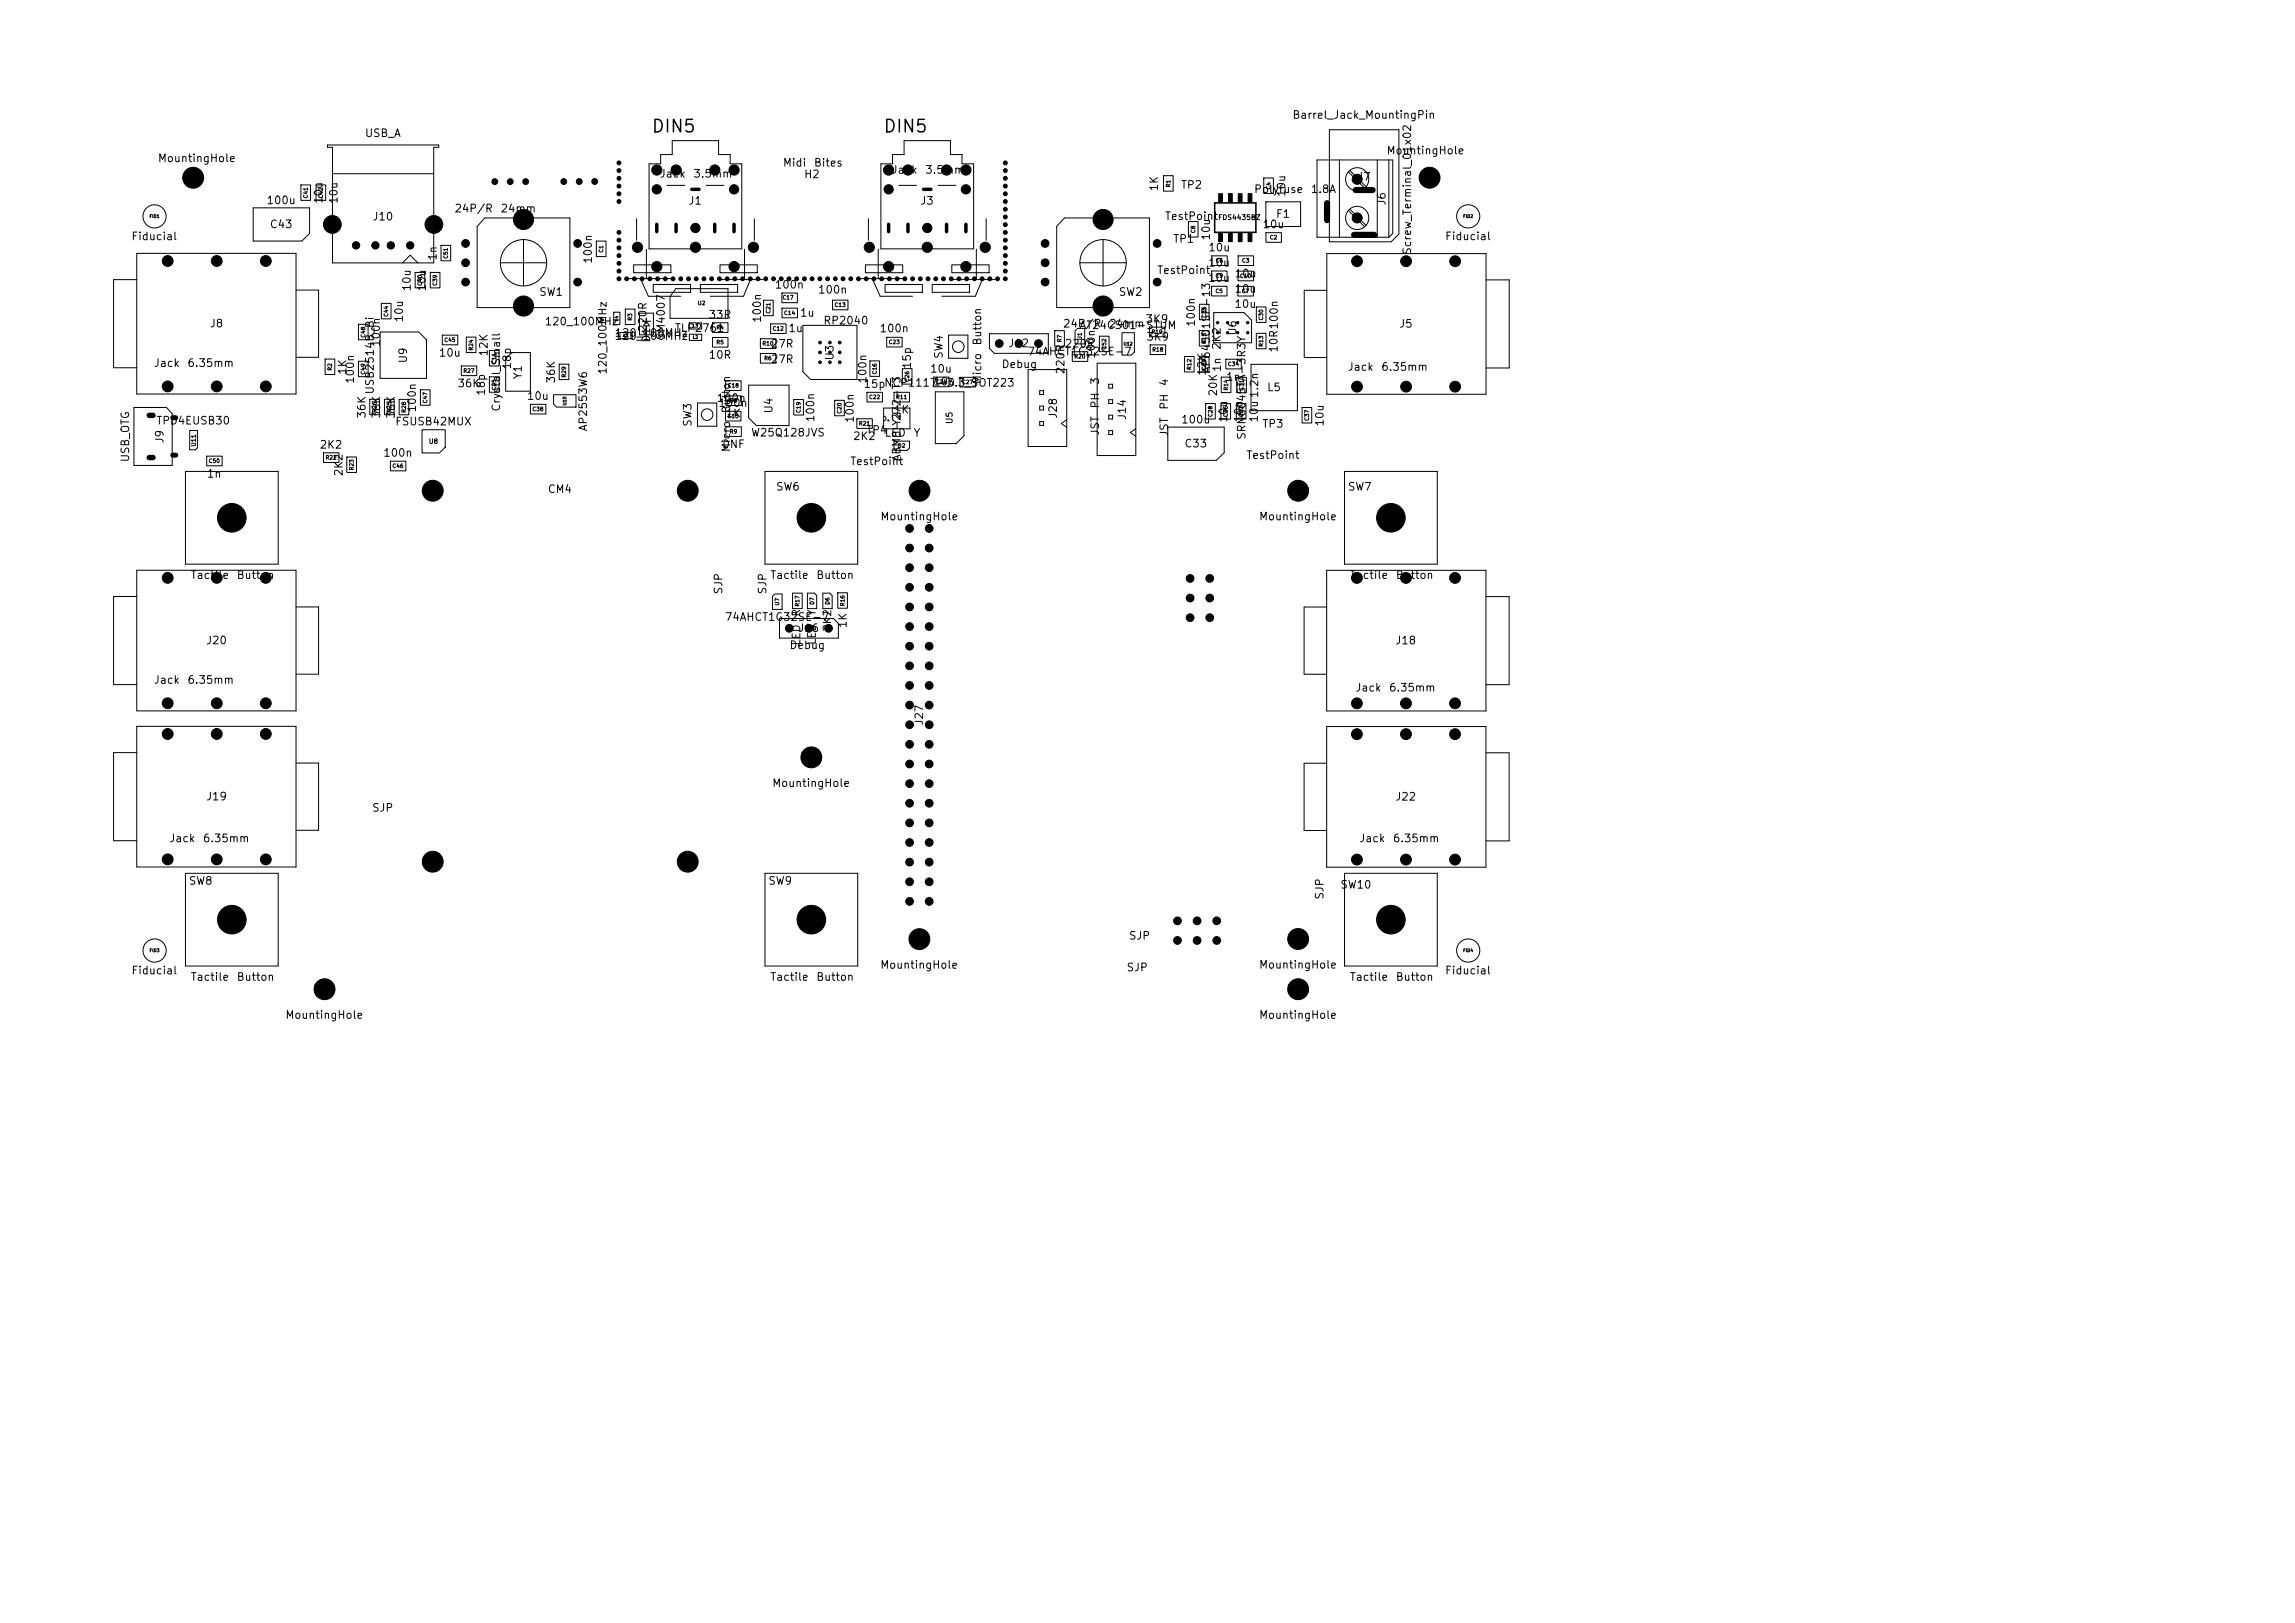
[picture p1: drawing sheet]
<svg xmlns="http://www.w3.org/2000/svg" width="297mm" height="210mm" viewBox="0 0 297 210" stroke-linecap="round" stroke-linejoin="round" font-family="sans-serif">
<defs><g id="words">
<g font-size="1.6">
<text x="84.2" y="17.5">DIN5</text>
<text x="114.2" y="17.5">DIN5</text>
</g>
<g font-size="1">
<text x="47.1" y="18">USB_A</text>
<text x="167.2" y="15.6">Barrel_Jack_MountingPin</text>
<text x="20.4" y="21.2">MountingHole</text>
<text x="23.9" y="23.7">H1</text>
<text x="85.3" y="23.2">Jack</text>
<text x="89.6" y="23.2">3.5mm</text>
<text x="101.2" y="21.8">Midi</text>
<text x="104" y="23.3">H2</text>
<text x="105.2" y="21.8">Bites</text>
<text x="115.3" y="22.7">Jack</text>
<text x="119.6" y="22.7">3.5mm</text>
<text x="175.6" y="23.6">J7</text>
<text x="179.4" y="20.2">MountingHole</text>
<text x="183.9" y="23.7">H3</text>
<text x="34.4" y="26.7">100u</text>
<text x="34.8" y="29.8">C43</text>
<text x="42" y="26.5" transform="rotate(-90 42 26.5)">10u</text>
<text x="43.9" y="26.5" transform="rotate(-90 43.9 26.5)">10u</text>
<text x="48.1" y="28.8">J10</text>
<text x="58.7" y="27.7">24P/R</text>
<text x="64.7" y="27.7">24mm</text>
<text x="89" y="26.7">J1</text>
<text x="119" y="26.7">J3</text>
<text x="150.1" y="24.8" transform="rotate(-90 150.1 24.8)">1K</text>
<text x="150.7" y="28.7">TestPoint</text>
<text x="152.7" y="24.7">TP2</text>
<text x="162.2" y="25.2">Polyfuse</text>
<text x="163.3" y="29.8">10u</text>
<text x="165" y="28.4">F1</text>
<text x="166.6" y="25.6" transform="rotate(-90 166.6 25.6)">10u</text>
<text x="169.6" y="25.2">1.8A</text>
<text x="179.6" y="26.7" transform="rotate(-90 179.6 26.7)">J6</text>
<text x="16.9" y="31.3">Fiducial</text>
<text x="56.7" y="33.8" transform="rotate(-90 56.7 33.8)">1n</text>
<text x="76.8" y="34.2" transform="rotate(-90 76.8 34.2)">100n</text>
<text x="149.7" y="35.7">TestPoint</text>
<text x="151.7" y="31.7">TP1</text>
<text x="156.3" y="34.7">10u</text>
<text x="156.3" y="32.8">10u</text>
<text x="156.8" y="31.2" transform="rotate(-90 156.8 31.2)">10u</text>
<text x="182.9" y="33" transform="rotate(-90 182.9 33)">Screw_Terminal_01x02</text>
<text x="186.9" y="31.3">Fiducial</text>
<text x="52.4" y="41.8" transform="rotate(-90 52.4 41.8)">10u</text>
<text x="53.4" y="37.8" transform="rotate(-90 53.4 37.8)">10u</text>
<text x="55.4" y="37.8" transform="rotate(-90 55.4 37.8)">10u</text>
<text x="69.7" y="38.5">SW1</text>
<text x="91.6" y="41.5">33R</text>
<text x="98.7" y="41.9" transform="rotate(-90 98.7 41.9)">100n</text>
<text x="100.2" y="37.6">100n</text>
<text x="103.4" y="41.2">1u</text>
<text x="105.8" y="38.2">100n</text>
<text x="144.7" y="38.5">SW2</text>
<text x="156.3" y="36.7">10u</text>
<text x="159.7" y="40.1">10u</text>
<text x="159.7" y="38.1">10u</text>
<text x="159.7" y="36.1">10u</text>
<text x="19.8" y="47.7">Jack</text>
<text x="24.2" y="47.7">6.35mm</text>
<text x="27.1" y="42.6">J8</text>
<text x="49.4" y="45" transform="rotate(-90 49.4 45)">100n</text>
<text x="52.9" y="47.1" transform="rotate(-90 52.9 47.1)">U9</text>
<text x="56.7" y="46.4">10u</text>
<text x="63.3" y="46.2" transform="rotate(-90 63.3 46.2)">12K</text>
<text x="66.4" y="47.9" transform="rotate(-90 66.4 47.9)">18p</text>
<text x="70.4" y="42.3">120_100MHz</text>
<text x="79.4" y="43.8">120_100MHz</text>
<text x="79.4" y="44.2">120_100MHz</text>
<text x="83.9" y="43" transform="rotate(-90 83.9 43)">220R</text>
<text x="84.4" y="44.4" transform="rotate(-90 84.4 44.4)">D1</text>
<text x="86.3" y="44.1" transform="rotate(-90 86.3 44.1)">SM4007</text>
<text x="87.2" y="43.2">TLP2761</text>
<text x="91.6" y="46.7">10R</text>
<text x="99.7" y="45.2">27R</text>
<text x="99.7" y="47.2">27R</text>
<text x="101.9" y="43.2">1u</text>
<text x="106.5" y="42.2">RP2040</text>
<text x="108.1" y="46.7" transform="rotate(-90 108.1 46.7)">U3</text>
<text x="113.7" y="43.2">100n</text>
<text x="118.1" y="47.8" transform="rotate(-90 118.1 47.8)">15p</text>
<text x="122.2" y="46.5" transform="rotate(-90 122.2 46.5)">SW4</text>
<text x="127.2" y="44.8" transform="rotate(-90 127.2 44.8)">Button</text>
<text x="129.5" y="47.9">Debug</text>
<text x="130.4" y="45.2">J12</text>
<text x="132.9" y="46.2">74AHCT1G32SE-7</text>
<text x="137.5" y="42.6">24P/R</text>
<text x="137.7" y="45.2">220R</text>
<text x="139.6" y="42.8">AT24CS01-STUM</text>
<text x="141.9" y="46.5" transform="rotate(-90 141.9 46.5)">100n</text>
<text x="143.4" y="42.6">24mm</text>
<text x="148.2" y="42">3K9</text>
<text x="148.3" y="44.3">3K9</text>
<text x="154.9" y="42.4" transform="rotate(-90 154.9 42.4)">100n</text>
<text x="158.2" y="45.3" transform="rotate(-90 158.2 45.3)">2K2</text>
<text x="160.2" y="43.5" transform="rotate(-90 160.2 43.5)">U6</text>
<text x="165.6" y="45.7" transform="rotate(-90 165.6 45.7)">10R100n</text>
<text x="181" y="42.6">J5</text>
<text x="45.1" y="48.6" transform="rotate(-90 45.1 48.6)">1K</text>
<text x="46.1" y="49.7" transform="rotate(-90 46.1 49.7)">100n</text>
<text x="48.6" y="51.1" transform="rotate(-90 48.6 51.1)">USB2514B_Bi</text>
<text x="54.1" y="53.4" transform="rotate(-90 54.1 53.4)">100n</text>
<text x="59.1" y="50.4">36K</text>
<text x="63" y="51.3" transform="rotate(-90 63 51.3)">18p</text>
<text x="65" y="53.3" transform="rotate(-90 65 53.3)">Crystal_Small</text>
<text x="67.8" y="49.1" transform="rotate(-90 67.8 49.1)">Y1</text>
<text x="68.1" y="52">10u</text>
<text x="72.1" y="49.7" transform="rotate(-90 72.1 49.7)">36K</text>
<text x="78.7" y="48.6" transform="rotate(-90 78.7 48.6)">120_100MHz</text>
<text x="92.7" y="52.3">100n</text>
<text x="92.9" y="52.9">100n</text>
<text x="94.7" y="53.6" transform="rotate(-90 94.7 53.6)">Button</text>
<text x="100.2" y="53.6" transform="rotate(-90 100.2 53.6)">U4</text>
<text x="111.7" y="50.4">15pNCP1117-3.3_SOT223</text>
<text x="112.4" y="49.7" transform="rotate(-90 112.4 49.7)">100n</text>
<text x="115.6" y="53.8">1K</text>
<text x="120.3" y="48.5">10u</text>
<text x="120.7" y="50.1">10u</text>
<text x="127.2" y="49.8" transform="rotate(-90 127.2 49.8)">Micro</text>
<text x="138" y="48.5" transform="rotate(-90 138 48.5)">220R</text>
<text x="142.5" y="52.9" transform="rotate(-90 142.5 52.9)">PH</text>
<text x="142.5" y="49.9" transform="rotate(-90 142.5 49.9)">3</text>
<text x="151.4" y="53.1" transform="rotate(-90 151.4 53.1)">PH</text>
<text x="151.4" y="50" transform="rotate(-90 151.4 50)">4</text>
<text x="156.3" y="48.7" transform="rotate(-90 156.3 48.7)">12K</text>
<text x="156.8" y="48.4" transform="rotate(-90 156.8 48.4)">AP64501SP-13</text>
<text x="157.7" y="51.4" transform="rotate(-90 157.7 51.4)">20K</text>
<text x="158.2" y="48.2" transform="rotate(-90 158.2 48.2)">1n</text>
<text x="158.6" y="49.5">1n</text>
<text x="163.9" y="50.9">L5</text>
<text x="174.3" y="48.2">Jack</text>
<text x="178.7" y="48.2">6.35mm</text>
<text x="17" y="59.9" transform="rotate(-90 17 59.9)">USB_OTG</text>
<text x="20.1" y="55.2">TPD4EUSB30</text>
<text x="21.4" y="57.5" transform="rotate(-90 21.4 57.5)">J9</text>
<text x="41.3" y="58.3">2K2</text>
<text x="47.6" y="54.2" transform="rotate(-90 47.6 54.2)">36K</text>
<text x="49.5" y="54.2" transform="rotate(-90 49.5 54.2)">36K</text>
<text x="49.5" y="59.3">100n</text>
<text x="51.1" y="55.3">FSUSB42MUX</text>
<text x="51.4" y="54.3" transform="rotate(-90 51.4 54.3)">36K</text>
<text x="76.2" y="55.9" transform="rotate(-90 76.2 55.9)">AP2553W6</text>
<text x="89.7" y="55.3" transform="rotate(-90 89.7 55.3)">SW3</text>
<text x="93.4" y="58.2">DNF</text>
<text x="93.8" y="54.2">1K</text>
<text x="94.7" y="58.6" transform="rotate(-90 94.7 58.6)">Micro</text>
<text x="97.1" y="56.7">W25Q128JVS</text>
<text x="105.6" y="54.7" transform="rotate(-90 105.6 54.7)">100n</text>
<text x="110.3" y="57.2">2K2</text>
<text x="110.7" y="54.8" transform="rotate(-90 110.7 54.8)">100n</text>
<text x="112" y="56.4">TP4</text>
<text x="114.4" y="56.8">LED</text>
<text x="116.8" y="59.8" transform="rotate(-90 116.8 59.8)">ABM8-272-T3</text>
<text x="116.8" y="55.2" transform="rotate(-90 116.8 55.2)">Y2</text>
<text x="118.1" y="56.8">Y</text>
<text x="137" y="54.3" transform="rotate(-90 137 54.3)">J28</text>
<text x="142.5" y="56.4" transform="rotate(-90 142.5 56.4)">JST</text>
<text x="146" y="54.4" transform="rotate(-90 146 54.4)">J14</text>
<text x="151.4" y="56.6" transform="rotate(-90 151.4 56.6)">JST</text>
<text x="152.8" y="55">100u</text>
<text x="153.2" y="58.1">C33</text>
<text x="159.1" y="54.7" transform="rotate(-90 159.1 54.7)">10u</text>
<text x="161" y="54.8" transform="rotate(-90 161 54.8)">10u</text>
<text x="161.2" y="59.6">TestPoint</text>
<text x="161.4" y="57" transform="rotate(-90 161.4 57)">SRN6045TA-3R3Y</text>
<text x="163" y="54.7" transform="rotate(-90 163 54.7)">10u 1.2n</text>
<text x="163.3" y="55.6">TP3</text>
<text x="171.5" y="55.3" transform="rotate(-90 171.5 55.3)">10u</text>
<text x="26.7" y="62.1">1n</text>
<text x="44.6" y="61.7" transform="rotate(-90 44.6 61.7)">2K2</text>
<text x="70.8" y="64">CM4</text>
<text x="100.4" y="63.7">SW6</text>
<text x="109.9" y="60.4">TestPoint</text>
<text x="117.9" y="64.2">H5</text>
<text x="166.9" y="64.2">H4</text>
<text x="174.4" y="63.7">SW7</text>
<text x="113.9" y="67.6">MountingHole</text>
<text x="162.9" y="67.6">MountingHole</text>
<text x="24.6" y="75.2">Tactile</text>
<text x="30.6" y="75.2">Button</text>
<text x="93.7" y="77" transform="rotate(-90 93.7 77)">SJP</text>
<text x="99.4" y="77" transform="rotate(-90 99.4 77)">SJP</text>
<text x="99.6" y="75.2">Tactile</text>
<text x="105.6" y="75.2">Button</text>
<text x="174.6" y="75.2">Tactile</text>
<text x="180.6" y="75.2">Button</text>
<text x="26.6" y="83.6">J20</text>
<text x="93.7" y="80.6">74AHCT1G32SE-7</text>
<text x="103.2" y="82">J16</text>
<text x="103.8" y="83.6" transform="rotate(-90 103.8 83.6)">LED</text>
<text x="103.8" y="79.9" transform="rotate(-90 103.8 79.9)">R</text>
<text x="105.8" y="83.5" transform="rotate(-90 105.8 83.5)">LED</text>
<text x="105.8" y="79.8" transform="rotate(-90 105.8 79.8)">Y</text>
<text x="107.8" y="81.8" transform="rotate(-90 107.8 81.8)">2K2</text>
<text x="109.8" y="81.4" transform="rotate(-90 109.8 81.4)">1K</text>
<text x="180.5" y="83.6">J18</text>
<text x="19.8" y="88.7">Jack</text>
<text x="24.2" y="88.7">6.35mm</text>
<text x="102.1" y="84.2">Debug</text>
<text x="175.3" y="89.7">Jack</text>
<text x="179.7" y="89.7">6.35mm</text>
<text x="119.7" y="94" transform="rotate(-90 119.7 94)">J27</text>
<text x="103.4" y="98.7">H16</text>
<text x="26.6" y="103.8">J19</text>
<text x="48.1" y="105.3">SJP</text>
<text x="99.9" y="102.1">MountingHole</text>
<text x="180.5" y="103.8">J22</text>
<text x="21.8" y="109.2">Jack</text>
<text x="26.2" y="109.2">6.35mm</text>
<text x="175.8" y="109.2">Jack</text>
<text x="180.2" y="109.2">6.35mm</text>
<text x="24.4" y="114.7">SW8</text>
<text x="99.4" y="114.7">SW9</text>
<text x="171.5" y="116.5" transform="rotate(-90 171.5 116.5)">SJP</text>
<text x="173.4" y="115.2">SW10</text>
<text x="113.8" y="125.6">MountingHole</text>
<text x="117.9" y="122.2">H6</text>
<text x="145.7" y="125.9">SJP</text>
<text x="146" y="121.8">SJP</text>
<text x="162.9" y="125.6">MountingHole</text>
<text x="166.9" y="122.2">H7</text>
<text x="16.9" y="126.3">Fiducial</text>
<text x="24.6" y="127.2">Tactile</text>
<text x="30.6" y="127.2">Button</text>
<text x="40.4" y="128.7">H14</text>
<text x="99.6" y="127.2">Tactile</text>
<text x="105.6" y="127.2">Button</text>
<text x="166.4" y="128.7">H15</text>
<text x="174.6" y="127.2">Tactile</text>
<text x="180.6" y="127.2">Button</text>
<text x="186.9" y="126.3">Fiducial</text>
<text x="36.9" y="132.1">MountingHole</text>
<text x="162.9" y="132.1">MountingHole</text>
</g>
<text font-size=".8" x="123.5" y="55" transform="rotate(-90 123.5 55)">U5</text>
<g font-size=".6">
<text x="157.6" y="28.6">FDS4435BZ</text>
<text x="55.4" y="57.6">U8</text>
</g>
<g font-size=".5">
<text x="39.9" y="25.7" transform="rotate(-90 39.9 25.7)">C41</text>
<text x="41.9" y="25.7" transform="rotate(-90 41.9 25.7)">C42</text>
<text x="151.6" y="24.3" transform="rotate(-90 151.6 24.3)">R1</text>
<text x="164.5" y="24.6" transform="rotate(-90 164.5 24.6)">C4</text>
<text x="58.1" y="33.5" transform="rotate(-90 58.1 33.5)">C51</text>
<text x="78.2" y="32.8" transform="rotate(-90 78.2 32.8)">C1</text>
<text x="154.8" y="30.2" transform="rotate(-90 154.8 30.2)">C8</text>
<text x="157.3" y="34.1">C6</text>
<text x="160.7" y="34.1">C3</text>
<text x="164.3" y="31.1">C2</text>
<text x="50.3" y="41.1" transform="rotate(-90 50.3 41.1)">C44</text>
<text x="54.7" y="37" transform="rotate(-90 54.7 37)">C40</text>
<text x="56.7" y="37" transform="rotate(-90 56.7 37)">C39</text>
<text x="81.9" y="41.6" transform="rotate(-90 81.9 41.6)">R3</text>
<text x="90.2" y="39.6">U2</text>
<text x="99.8" y="40.6" transform="rotate(-90 99.8 40.6)">C21</text>
<text x="101.2" y="38.9">C17</text>
<text x="101.4" y="40.9">C14</text>
<text x="107.9" y="39.8">C13</text>
<text x="156.2" y="41.2" transform="rotate(-90 156.2 41.2)">C35</text>
<text x="157.2" y="38">C5</text>
<text x="157.2" y="36.1">C9</text>
<text x="160.4" y="36.1">C10</text>
<text x="160.6" y="38.1">C7</text>
<text x="163.6" y="41.5" transform="rotate(-90 163.6 41.5)">C30</text>
<text x="47.4" y="43.8" transform="rotate(-90 47.4 43.8)">C48</text>
<text x="57.4" y="44.4">C45</text>
<text x="61.3" y="45.4" transform="rotate(-90 61.3 45.4)">R24</text>
<text x="64.3" y="47.2" transform="rotate(-90 64.3 47.2)">C11</text>
<text x="92.7" y="42.8">R4</text>
<text x="92.7" y="44.7">R5</text>
<text x="98.6" y="44.8">R10</text>
<text x="98.8" y="46.7">R6</text>
<text x="99.9" y="42.9">C12</text>
<text x="115" y="44.6">C23</text>
<text x="137.5" y="44.3" transform="rotate(-90 137.5 44.3)">R7</text>
<text x="139" y="46.5">R20</text>
<text x="140.1" y="44.1" transform="rotate(-90 140.1 44.1)">U1</text>
<text x="143.3" y="45.3" transform="rotate(-90 143.3 45.3)">C52</text>
<text x="149" y="43.3">R19</text>
<text x="149.1" y="45.6">R18</text>
<text x="154.3" y="47.9" transform="rotate(-90 154.3 47.9)">R12</text>
<text x="156.2" y="44.6" transform="rotate(-90 156.2 44.6)">R15</text>
<text x="156.2" y="48" transform="rotate(-90 156.2 48)">C29</text>
<text x="158.8" y="47.5">C34</text>
<text x="163.6" y="44.9" transform="rotate(-90 163.6 44.9)">R13</text>
<text x="43.1" y="48" transform="rotate(-90 43.1 48)">R2</text>
<text x="47.4" y="48.5" transform="rotate(-90 47.4 48.5)">C49</text>
<text x="48.9" y="53.5" transform="rotate(-90 48.9 53.5)">R26</text>
<text x="50.7" y="53.5" transform="rotate(-90 50.7 53.5)">R25</text>
<text x="52.6" y="53.5" transform="rotate(-90 52.6 53.5)">R28</text>
<text x="55.4" y="52.2" transform="rotate(-90 55.4 52.2)">C47</text>
<text x="59.9" y="48.4">R27</text>
<text x="64.3" y="50.6" transform="rotate(-90 64.3 50.6)">C25</text>
<text x="68.8" y="53.3">C38</text>
<text x="73.4" y="48.9" transform="rotate(-90 73.4 48.9)">R29</text>
<text x="94.1" y="50.3">C18</text>
<text x="94.4" y="52.2">R8</text>
<text x="103.7" y="53.5" transform="rotate(-90 103.7 53.5)">C19</text>
<text x="109" y="53.6" transform="rotate(-90 109 53.6)">C20</text>
<text x="112.4" y="51.8">C22</text>
<text x="113.6" y="48.5" transform="rotate(-90 113.6 48.5)">C16</text>
<text x="115.9" y="51.8">R11</text>
<text x="117.8" y="49.5" transform="rotate(-90 117.8 49.5)">C26</text>
<text x="121" y="49.8">C24</text>
<text x="124.4" y="49.8">C27</text>
<text x="159" y="50.6" transform="rotate(-90 159 50.6)">R14</text>
<text x="161" y="50.6" transform="rotate(-90 161 50.6)">C31</text>
<text x="25.5" y="57.9" transform="rotate(-90 25.5 57.9)">U11</text>
<text x="42.1" y="59.6">R22</text>
<text x="94.1" y="54.2">C15</text>
<text x="94.4" y="56.2">R9</text>
<text x="111.1" y="55.2">R21</text>
<text x="116.1" y="58.1">D2</text>
<text x="157" y="54" transform="rotate(-90 157 54)">C28</text>
<text x="159" y="54" transform="rotate(-90 159 54)">C36</text>
<text x="161" y="54" transform="rotate(-90 161 54)">C32</text>
<text x="169.5" y="54.5" transform="rotate(-90 169.5 54.5)">C37</text>
<text x="27" y="60">C50</text>
<text x="45.9" y="60.9" transform="rotate(-90 45.9 60.9)">R23</text>
<text x="50.7" y="60.7">C46</text>
<text x="101" y="78.4" transform="rotate(-90 101 78.4)">U7</text>
<text x="103.6" y="78.5" transform="rotate(-90 103.6 78.5)">R17</text>
<text x="105.5" y="78.3" transform="rotate(-90 105.5 78.3)">D7</text>
<text x="107.5" y="78.3" transform="rotate(-90 107.5 78.3)">D6</text>
<text x="109.4" y="78.5" transform="rotate(-90 109.4 78.5)">R16</text>
</g>
<g font-size=".4">
<text x="19.3" y="28.3">FID1</text>
<text x="189.3" y="28.3">FID2</text>
<text x="80.1" y="41.6" transform="rotate(-90 80.1 41.6)">L4</text>
<text x="80.6" y="43.7">L1</text>
<text x="89.6" y="43.9">L2</text>
<text x="89.6" y="42.5">L3</text>
<text x="145.4" y="44.8">U12</text>
<text x="73.4" y="52.5" transform="rotate(-90 73.4 52.5)">U10</text>
<text x="19.3" y="123.3">FID3</text>
<text x="189.3" y="123.3">FID4</text>
</g>
</g></defs>
<g fill="none" stroke="#000" stroke-width=".13">
<path d="M42.4 18.8h14.4v.3h-.7v14.9h-13.1v-14.9h-.6zM117 18.2h6v1.8h1.5v1.2h1.5v11h-12v-11h1.5v-1.2h1.5zM172 16.8h9v13.5l-1 1h-8zM17.7 36.2h-3v11.4h3M17.7 32.8h20.6v18.2h-20.6zM32.8 26.9h7.3v3.3l-1 1h-6.3zM38.3 37.5h2.9v8.7h-2.9M38.9 23.9h1.3v2h-1.3zM40.9 23.9h1.2v2h-1.2zM43 22.5h13.1M49.4 39.3h1.2v2h-1.2zM52.1 34l1-1 1 1"/>
<path d="M53.7 35.3h1.3v2h-1.3zM55.7 35.3h1.2v2h-1.2zM57.1 31.8h1.2v2h-1.2zM62.7 28.2h11.1v11.6h-12.1v-10.5zM64.8 34h5.9M67.7 31v6M77.2 31.2h1.2v2h-1.2zM80.9 40h1.3v2h-1.3zM81.2 36.1h5.6M82 34.3h4.8v1h-4.8zM82.4 28.3v2.8M82.9 36.1l1 2.2h4.2"/>
<path d="M83.6 32.2v3.9M84 21.2h1.5v-1.2h1.5v-1.8h6v1.8h1.5v1.2h1.5v11h-12zM84.5 36.8h4.9v1h-4.9zM86.3 24h2.3M87.5 37.4h6.7v3.8h-7.5v-2.8zM90.6 36.8h4.9v1h-4.9zM91.4 24h2.3M93.2 36.2h5.6M93.2 34.3h4.8v1h-4.8zM96.3 32.2v4M97.1 36.2l-.9 2.1h-4.3M97.6 28.3v2.8"/>
<path d="M98.8 38.9h1.3v2h-1.3zM101.2 37.9h2v1.3h-2zM101.2 39.9h2v1.2h-2zM107.7 38.8h2v1.3h-2zM111.2 36.1h5.6M112 34.3h4.8v1h-4.8zM112.4 28.3v2.8M112.9 36.1l1 2.2h4.2M113.6 32.2v3.9M114.5 36.8h4.9v1h-4.9zM116.3 24h2.3M120.6 36.8h4.9v1h-4.9z"/>
<path d="M121.4 24h2.3M123.2 36.2h5.6M123.2 34.3h4.8v1h-4.8zM126.3 32.2v4M127.1 36.2l-.9 2.1h-4.3M127.6 28.3v2.8M137.8 28.2h10.9v11.6h-12v-10.5zM139.7 34h6M142.8 31v6M150.6 22.7h1.2v2h-1.2zM153.8 28.7h1.2v2h-1.2zM155.2 39.4h1.3v2h-1.3z"/>
<path d="M156.8 37h2v1.3h-2zM156.8 35.1h2v1.2h-2zM156.8 33.1h2v1.3h-2zM160.2 37.1h2v1.2h-2zM160.2 35.1h2v1.2h-2zM160.2 33.1h2v1.3h-2zM162.6 39.7h1.2v2h-1.2zM163.5 23h1.3v2h-1.3zM163.8 26.1h4.5v3.2h-4.5zM163.8 30.1h2v1.3h-2zM170.4 20.7h9.8v9.5l-.5 .5h-9.3zM171.7 32.8h20.6v18.2h-20.6z"/>
<path d="M171.7 37.6h-2.9v8.7h2.9M173.3 20.7v10M174.5 22.2l2.1 2.1M174.5 27.2l2.1 2.1M174.7 22.1l2.1 2.1M174.7 27.1l2.1 2.1M178.2 20.7v10M179.7 20.7v10M192.3 36.2h3v11.4h-3M17.3 52.7h4.2l.8 .8v6.7h-5zM24.5 55.7h1v2.3l-.2 .2h-.8zM26.8 59h2v1.3h-2z"/>
<path d="M41.9 58.6h2v1.2h-2zM42.1 46.5h1.2v2h-1.2zM44.9 59.1h1.2v2h-1.2zM46.4 42h1.2v2h-1.2zM46.4 46.7h1.2v2h-1.2zM47.9 51.7h1.2v2h-1.2zM49.2 43h5l1 1v5h-6zM49.8 51.7h1.2v2h-1.2zM50.5 59.7h2v1.2h-2zM51.7 51.7h1.2v2h-1.2zM54.4 50.4h1.3v2h-1.3zM54.6 55.6h3v2.3l-.7 .7h-2.3z"/>
<path d="M57.2 43.4h2v1.2h-2zM59.7 47.4h2v1.2h-2zM60.3 43.6h1.3v2h-1.3zM63.3 45.4h1.3v2h-1.3zM63.3 48.8h1.3v2h-1.3zM66.2 45.6h2.4v5h-3.2v-4.2zM68.6 52.3h2v1.3h-2zM71.6 51.1h2.9v1.6h-2.5l-.4-.4zM72.4 47.1h1.2v2h-1.2zM79.4 40.4h.8v1.6h-.8zM80.2 43h1.6v.8h-1.6zM82.8 40.5h1.8v2.8h-1.8z"/>
<path d="M83.1 41.6h1.1M83.7 41.6l.4 .6h-.8zM83.7 41.2v.4M83.7 42.2v.5M89.2 43.2h1.6v.8h-1.6zM89.2 41.8h1.6v.8h-1.6zM90.3 52.2h2.5v3h-2.5zM92.2 41.8h2v1.2h-2zM92.2 43.7h2v1.2h-2zM93.9 53.2h2v1.3h-2zM93.9 49.3h2v1.2h-2zM93.9 55.2h2v1.3h-2z"/>
<path d="M93.9 51.2h2v1.3h-2zM96.9 49.8h5.2v5.3h-4.2l-1-1zM98.4 43.8h2v1.3h-2zM98.4 45.7h2v1.3h-2zM99.7 41.9h2v1.3h-2zM102.7 51.7h1.3v2h-1.3zM103.9 42.1h7v7h-6l-1-1zM108 51.8h1.3v2h-1.3zM110.9 54.2h2v1.2h-2zM112.2 50.8h2v1.2h-2zM112.6 46.7h1.2v2h-1.2zM114.4 53.8l.2 .1 .1 .2-.1 .3-.2 .1"/>
<path d="M114.4 52.8h3.4v2.7h-3.4zM114.8 43.6h2v1.3h-2zM115.7 57.1h2v.9l-.3 .3h-1.7zM115.7 50.8h2v1.2h-2zM116.8 47.7h1.2v2h-1.2zM120.8 48.8h2v1.2h-2zM121 50.7h3.7v5.7l-1 1h-2.7zM122.8 43.4h2.5v3h-2.5zM124.2 48.8h2v1.3h-2zM128 43.2h7.7v2.5h-7l-.7-.6zM133 47.8h5v10h-5zM134.5 50.6h.6v.5h-.6z"/>
<path d="M134.5 52.6h.6v.5h-.6zM134.5 54.6h.6v.5h-.6zM136.5 42.8h1.2v2h-1.2zM138 54.3l-.7 .5 .7 .5M138.8 45.5h2v1.3h-2zM139.1 42.8l.3-.3h1v2h-1.3zM142 47h5v11.9h-5zM142.3 43.5h1.2v2h-1.2zM143.5 55.7h.5v.5h-.5zM143.5 49.7h.5v.5h-.5zM143.5 51.7h.5v.5h-.5zM143.5 53.7h.5v.5h-.5z"/>
<path d="M145.2 43h1.6v2.6l-.4 .4h-1.2zM147 55.5l-.7 .5 .7 .5M148.8 42.3h2v1.3h-2zM148.9 44.6h2v1.3h-2zM151.1 55.3h7.3v3.3l-1 1h-6.3zM153.3 46.1h1.2v2h-1.2zM155.2 42.8h1.3v2h-1.3zM155.2 46.2h1.3v2h-1.3zM156 52.2h1.3v2h-1.3zM157.1 40.5h3.9l1 .9v3h-4.9zM158 52.2h1.3v2h-1.3zM158 48.8h1.3v2h-1.3z"/>
<path d="M158.6 46.5h2v1.2h-2zM160 52.2h1.2v2h-1.2zM160 48.8h1.3v2h-1.3zM161.9 47.1h6v6h-6zM162.6 43.1h1.2v2h-1.2zM168.5 52.7h1.3v2h-1.3zM17.7 77.2h-3v11.4h3M17.7 73.8h20.6v18.2h-20.6zM24 61h12v12h-12zM38.3 78.5h2.9v8.7h-2.9M99 61h12v12h-12zM100 77.2l.3-.3h.9v2h-1.2z"/>
<path d="M102.6 76.8h1.2v2h-1.2zM104.5 76.8h.9l.3 .3v1.7h-1.2zM106.5 76.8h.9l.3 .3v1.7h-1.2zM108.4 76.7h1.3v2h-1.3zM171.7 73.8h20.6v18.2h-20.6zM171.7 78.5h-2.9v8.7h2.9M174 61h12v12h-12zM192.3 77.2h3v11.4h-3M17.7 97.4h-3v11.4h3M17.7 94h20.6v18.2h-20.6zM38.3 98.7h2.9v8.7h-2.9M100.9 80h7l.6 .7v1.9h-7.6z"/>
<path d="M171.7 94h20.6v18.2h-20.6zM171.7 98.8h-2.9v8.7h2.9M192.3 97.4h3v11.4h-3M24 113h12v12h-12zM99 113h12v12h-12zM174 113h12v12h-12z"/>
<circle cx="20" cy="28" r="1.5"/>
<circle cx="67.7" cy="34" r="3"/>
<circle cx="142.7" cy="34" r="3"/>
<circle cx="175.6" cy="23.2" r="1.5"/>
<circle cx="175.6" cy="28.2" r="1.5"/>
<circle cx="190" cy="28" r="1.5"/>
<circle cx="91.5" cy="53.6" r=".75"/>
<circle cx="115" cy="54.4" r=".08"/>
<circle cx="124" cy="44.9" r=".75"/>
<circle cx="20" cy="123" r="1.5"/>
<circle cx="190" cy="123" r="1.5"/>
</g>
<path d="M157.2 26.3h5.3v3.8h-5.3z" fill="none" stroke="#000" stroke-width=".2"/>
<g fill="#000" stroke="#000" stroke-width=".13">
<path d="M157.7 25.1h.5v1.1h-.5zM157.7 30.2h.5v1.1h-.5zM159 25.1h.5v1.1h-.5zM159 30.2h.5v1.1h-.5zM160.3 25.1h.4v1.1h-.4zM160.3 30.2h.4v1.1h-.4zM161.5 25.1h.5v1.1h-.5zM161.5 30.2h.5v1.1h-.5z"/>
<circle cx="21.7" cy="33.8" r=".7"/>
<circle cx="25" cy="23" r="1.35"/>
<circle cx="28" cy="33.8" r=".7"/>
<circle cx="34.4" cy="33.8" r=".7"/>
<circle cx="43" cy="29" r="1.15"/>
<circle cx="46.1" cy="31.8" r=".47"/>
<circle cx="48.6" cy="31.8" r=".47"/>
<circle cx="50.6" cy="31.8" r=".47"/>
<circle cx="53.1" cy="31.8" r=".47"/>
<circle cx="56.1" cy="29" r="1.15"/>
<circle cx="60.2" cy="36.5" r=".5"/>
<circle cx="60.2" cy="31.5" r=".5"/>
<circle cx="60.2" cy="34" r=".5"/>
<circle cx="64" cy="23.5" r=".38"/>
<circle cx="66" cy="23.5" r=".38"/>
<circle cx="67.7" cy="28.4" r="1.3"/>
<circle cx="67.7" cy="39.6" r="1.3"/>
<circle cx="68" cy="23.5" r=".38"/>
<circle cx="73" cy="23.5" r=".37"/>
<circle cx="74.8" cy="36.5" r=".5"/>
<circle cx="74.8" cy="31.5" r=".5"/>
<circle cx="75" cy="23.5" r=".37"/>
<circle cx="77" cy="23.5" r=".37"/>
<circle cx="80.1" cy="22.1" r=".25"/>
<circle cx="80.1" cy="25.1" r=".25"/>
<circle cx="80.1" cy="23.1" r=".25"/>
<circle cx="80.1" cy="24.1" r=".25"/>
<circle cx="80.1" cy="21.1" r=".25"/>
<circle cx="80.1" cy="26.1" r=".25"/>
<circle cx="80.1" cy="32.1" r=".25"/>
<circle cx="80.1" cy="33.1" r=".25"/>
<circle cx="80.1" cy="35.1" r=".25"/>
<circle cx="80.1" cy="30.1" r=".25"/>
<circle cx="80.1" cy="34.1" r=".25"/>
<circle cx="80.1" cy="31.1" r=".25"/>
<circle cx="80.1" cy="36.1" r=".25"/>
<circle cx="81.1" cy="36.1" r=".25"/>
<circle cx="82.1" cy="36.1" r=".25"/>
<circle cx="82.5" cy="32" r=".66"/>
<circle cx="83.1" cy="36.1" r=".25"/>
<circle cx="84.1" cy="36.1" r=".25"/>
<circle cx="85" cy="24.5" r=".6"/>
<circle cx="85" cy="34.5" r=".66"/>
<circle cx="85" cy="22" r=".66"/>
<circle cx="85.1" cy="36.1" r=".25"/>
<circle cx="86.1" cy="36.1" r=".25"/>
<circle cx="87.1" cy="36.1" r=".25"/>
<circle cx="87.5" cy="22" r=".66"/>
<circle cx="88.1" cy="36.1" r=".25"/>
<circle cx="89.1" cy="36.1" r=".25"/>
<circle cx="90" cy="29.5" r=".6"/>
<circle cx="90" cy="32" r=".66"/>
<circle cx="90.1" cy="36.1" r=".25"/>
<circle cx="91.1" cy="36.1" r=".25"/>
<circle cx="92.1" cy="36.1" r=".25"/>
<circle cx="92.5" cy="22" r=".66"/>
<circle cx="93.1" cy="36.1" r=".25"/>
<circle cx="94.1" cy="36.1" r=".25"/>
<circle cx="95" cy="24.5" r=".6"/>
<circle cx="95" cy="34.5" r=".66"/>
<circle cx="95" cy="22" r=".66"/>
<circle cx="95.1" cy="36.1" r=".25"/>
<circle cx="96.1" cy="36.1" r=".25"/>
<circle cx="97.1" cy="36.1" r=".25"/>
<circle cx="97.5" cy="32" r=".66"/>
<circle cx="98.1" cy="36.1" r=".25"/>
<circle cx="99.1" cy="36.1" r=".25"/>
<circle cx="100.1" cy="36.1" r=".25"/>
<circle cx="101.1" cy="36.1" r=".25"/>
<circle cx="102.1" cy="36.1" r=".25"/>
<circle cx="103.1" cy="36.1" r=".25"/>
<circle cx="104.1" cy="36.1" r=".25"/>
<circle cx="105.1" cy="36.1" r=".25"/>
<circle cx="106.1" cy="36.1" r=".25"/>
<circle cx="107.1" cy="36.1" r=".25"/>
<circle cx="108.1" cy="36.1" r=".25"/>
<circle cx="109.1" cy="36.1" r=".25"/>
<circle cx="110.1" cy="36.1" r=".25"/>
<circle cx="111.1" cy="36.1" r=".25"/>
<circle cx="112.1" cy="36.1" r=".25"/>
<circle cx="112.5" cy="32" r=".66"/>
<circle cx="113.1" cy="36.1" r=".25"/>
<circle cx="114.1" cy="36.1" r=".25"/>
<circle cx="115" cy="34.5" r=".66"/>
<circle cx="115" cy="22" r=".66"/>
<circle cx="115" cy="24.5" r=".6"/>
<circle cx="115.1" cy="36.1" r=".25"/>
<circle cx="116.1" cy="36.1" r=".25"/>
<circle cx="117.1" cy="36.1" r=".25"/>
<circle cx="117.5" cy="22" r=".66"/>
<circle cx="118.1" cy="36.1" r=".25"/>
<circle cx="119.1" cy="36.1" r=".25"/>
<circle cx="120" cy="29.5" r=".6"/>
<circle cx="120" cy="32" r=".66"/>
<circle cx="120.1" cy="36.1" r=".25"/>
<circle cx="121.1" cy="36.1" r=".25"/>
<circle cx="122.1" cy="36.1" r=".25"/>
<circle cx="122.5" cy="22" r=".66"/>
<circle cx="123.1" cy="36.1" r=".25"/>
<circle cx="124.1" cy="36.1" r=".25"/>
<circle cx="125" cy="34.5" r=".66"/>
<circle cx="125" cy="22" r=".66"/>
<circle cx="125" cy="24.5" r=".6"/>
<circle cx="125.1" cy="36.1" r=".25"/>
<circle cx="126.1" cy="36.1" r=".25"/>
<circle cx="127.1" cy="36.1" r=".25"/>
<circle cx="127.5" cy="32" r=".66"/>
<circle cx="128.1" cy="36.1" r=".25"/>
<circle cx="129.1" cy="36.1" r=".25"/>
<circle cx="130.1" cy="28.1" r=".25"/>
<circle cx="130.1" cy="27.1" r=".25"/>
<circle cx="130.1" cy="22.1" r=".25"/>
<circle cx="130.1" cy="25.1" r=".25"/>
<circle cx="130.1" cy="23.1" r=".25"/>
<circle cx="130.1" cy="24.1" r=".25"/>
<circle cx="130.1" cy="26.1" r=".25"/>
<circle cx="130.1" cy="21.1" r=".25"/>
<circle cx="130.1" cy="32.1" r=".25"/>
<circle cx="130.1" cy="35.1" r=".25"/>
<circle cx="130.1" cy="33.1" r=".25"/>
<circle cx="130.1" cy="30.1" r=".25"/>
<circle cx="130.1" cy="34.1" r=".25"/>
<circle cx="130.1" cy="29.1" r=".25"/>
<circle cx="130.1" cy="36.1" r=".25"/>
<circle cx="130.1" cy="31.1" r=".25"/>
<circle cx="135.3" cy="36.5" r=".5"/>
<circle cx="135.3" cy="31.5" r=".5"/>
<circle cx="135.3" cy="34" r=".5"/>
<circle cx="142.8" cy="28.4" r="1.3"/>
<circle cx="142.8" cy="39.6" r="1.3"/>
<circle cx="149.7" cy="31.5" r=".5"/>
<circle cx="149.7" cy="36.5" r=".5"/>
<circle cx="175.6" cy="33.8" r=".7"/>
<circle cx="175.6" cy="23.2" r=".65"/>
<circle cx="175.6" cy="28.2" r=".65"/>
<circle cx="182" cy="33.8" r=".7"/>
<circle cx="185" cy="23" r="1.35"/>
<circle cx="188.3" cy="33.8" r=".7"/>
<circle cx="21.7" cy="50" r=".7"/>
<circle cx="28" cy="50" r=".7"/>
<circle cx="34.4" cy="50" r=".7"/>
<circle cx="106.1" cy="46.9" r=".17"/>
<circle cx="106.1" cy="44.3" r=".17"/>
<circle cx="106.1" cy="45.6" r=".17"/>
<circle cx="107.4" cy="46.9" r=".17"/>
<circle cx="107.4" cy="45.6" r=".17"/>
<circle cx="107.4" cy="44.3" r=".17"/>
<circle cx="108.7" cy="46.9" r=".17"/>
<circle cx="108.7" cy="44.3" r=".17"/>
<circle cx="108.7" cy="45.6" r=".17"/>
<circle cx="129.3" cy="44.5" r=".5"/>
<circle cx="131.9" cy="44.5" r=".5"/>
<circle cx="134.4" cy="44.5" r=".5"/>
<circle cx="157.6" cy="41.8" r=".15"/>
<circle cx="157.6" cy="43.1" r=".15"/>
<circle cx="158.9" cy="43.1" r=".15"/>
<circle cx="158.9" cy="41.8" r=".15"/>
<circle cx="160.2" cy="43.1" r=".15"/>
<circle cx="160.2" cy="41.8" r=".15"/>
<circle cx="161.5" cy="43.1" r=".15"/>
<circle cx="161.5" cy="41.8" r=".15"/>
<circle cx="175.6" cy="50" r=".7"/>
<circle cx="182" cy="50" r=".7"/>
<circle cx="188.3" cy="50" r=".7"/>
<circle cx="21.7" cy="74.8" r=".7"/>
<circle cx="28" cy="74.8" r=".7"/>
<circle cx="30" cy="67" r="1.85"/>
<circle cx="34.4" cy="74.8" r=".7"/>
<circle cx="56" cy="63.5" r="1.35"/>
<circle cx="89" cy="63.5" r="1.35"/>
<circle cx="105" cy="67" r="1.85"/>
<circle cx="117.7" cy="70.9" r=".5"/>
<circle cx="117.7" cy="78.5" r=".5"/>
<circle cx="117.7" cy="76" r=".5"/>
<circle cx="117.7" cy="68.4" r=".5"/>
<circle cx="117.7" cy="73.5" r=".5"/>
<circle cx="119" cy="63.5" r="1.35"/>
<circle cx="120.3" cy="68.4" r=".5"/>
<circle cx="120.3" cy="78.5" r=".5"/>
<circle cx="120.3" cy="70.9" r=".5"/>
<circle cx="120.3" cy="73.5" r=".5"/>
<circle cx="120.3" cy="76" r=".5"/>
<circle cx="154" cy="74.8" r=".5"/>
<circle cx="154" cy="77.4" r=".5"/>
<circle cx="154" cy="79.9" r=".5"/>
<circle cx="156.6" cy="74.8" r=".5"/>
<circle cx="156.6" cy="77.4" r=".5"/>
<circle cx="156.6" cy="79.9" r=".5"/>
<circle cx="168" cy="63.5" r="1.35"/>
<circle cx="175.6" cy="74.8" r=".7"/>
<circle cx="180" cy="67" r="1.85"/>
<circle cx="181.9" cy="74.8" r=".7"/>
<circle cx="188.3" cy="74.8" r=".7"/>
<circle cx="21.7" cy="95" r=".7"/>
<circle cx="21.7" cy="91" r=".7"/>
<circle cx="28" cy="95" r=".7"/>
<circle cx="28" cy="91" r=".7"/>
<circle cx="34.4" cy="95" r=".7"/>
<circle cx="34.4" cy="91" r=".7"/>
<circle cx="102.1" cy="81.3" r=".5"/>
<circle cx="104.7" cy="81.3" r=".5"/>
<circle cx="105" cy="98" r="1.35"/>
<circle cx="107.2" cy="81.3" r=".5"/>
<circle cx="117.7" cy="83.6" r=".5"/>
<circle cx="117.7" cy="93.8" r=".5"/>
<circle cx="117.7" cy="86.2" r=".5"/>
<circle cx="117.7" cy="91.2" r=".5"/>
<circle cx="117.7" cy="98.9" r=".5"/>
<circle cx="117.7" cy="81.1" r=".5"/>
<circle cx="117.7" cy="96.3" r=".5"/>
<circle cx="117.7" cy="88.7" r=".5"/>
<circle cx="120.3" cy="96.3" r=".5"/>
<circle cx="120.3" cy="93.8" r=".5"/>
<circle cx="120.3" cy="81.1" r=".5"/>
<circle cx="120.3" cy="83.6" r=".5"/>
<circle cx="120.3" cy="86.2" r=".5"/>
<circle cx="120.3" cy="88.7" r=".5"/>
<circle cx="120.3" cy="98.9" r=".5"/>
<circle cx="120.3" cy="91.2" r=".5"/>
<circle cx="175.6" cy="91" r=".7"/>
<circle cx="175.6" cy="95" r=".7"/>
<circle cx="181.9" cy="91" r=".7"/>
<circle cx="181.9" cy="95" r=".7"/>
<circle cx="188.3" cy="91" r=".7"/>
<circle cx="188.3" cy="95" r=".7"/>
<circle cx="21.7" cy="111.2" r=".7"/>
<circle cx="28" cy="111.2" r=".7"/>
<circle cx="30" cy="119" r="1.85"/>
<circle cx="34.4" cy="111.2" r=".7"/>
<circle cx="56" cy="111.5" r="1.35"/>
<circle cx="89" cy="111.5" r="1.35"/>
<circle cx="105" cy="119" r="1.85"/>
<circle cx="117.7" cy="114.1" r=".5"/>
<circle cx="117.7" cy="103.9" r=".5"/>
<circle cx="117.7" cy="101.4" r=".5"/>
<circle cx="117.7" cy="116.6" r=".5"/>
<circle cx="117.7" cy="106.5" r=".5"/>
<circle cx="117.7" cy="109" r=".5"/>
<circle cx="117.7" cy="111.6" r=".5"/>
<circle cx="120.3" cy="103.9" r=".5"/>
<circle cx="120.3" cy="111.6" r=".5"/>
<circle cx="120.3" cy="101.4" r=".5"/>
<circle cx="120.3" cy="109" r=".5"/>
<circle cx="120.3" cy="116.6" r=".5"/>
<circle cx="120.3" cy="106.5" r=".5"/>
<circle cx="120.3" cy="114.1" r=".5"/>
<circle cx="152.4" cy="119.2" r=".5"/>
<circle cx="154.9" cy="119.2" r=".5"/>
<circle cx="157.5" cy="119.2" r=".5"/>
<circle cx="175.6" cy="111.2" r=".7"/>
<circle cx="180" cy="119" r="1.85"/>
<circle cx="181.9" cy="111.2" r=".7"/>
<circle cx="188.3" cy="111.2" r=".7"/>
<circle cx="42" cy="128" r="1.35"/>
<circle cx="119" cy="121.5" r="1.35"/>
<circle cx="152.4" cy="121.7" r=".5"/>
<circle cx="154.9" cy="121.7" r=".5"/>
<circle cx="157.5" cy="121.7" r=".5"/>
<circle cx="168" cy="121.5" r="1.35"/>
<circle cx="168" cy="128" r="1.35"/>
</g>
<path d="M85 29v1M87.5 29v1M89.5 24.5h1M92.5 29v1M95 29v1M115 29v1M117.5 29v1M119.5 24.5h1M122.5 29v1M125 29v1" fill="none" stroke="#000" stroke-width=".45"/>
<path d="M171.7 26.3v2.2M175.2 30.4h2.6M175.4 24.6h2.2" fill="none" stroke="#000" stroke-width=".8"/>
<path d="M19.3 53.7h.5M19.3 59.2h.5" fill="none" stroke="#000" stroke-width=".7"/>
<path d="M22.4 54.1h.4M22.4 58.9h.4" fill="none" stroke="#000" stroke-width=".65"/>
<use href="#words"/>
</svg>
